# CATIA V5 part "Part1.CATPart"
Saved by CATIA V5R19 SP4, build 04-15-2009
Part number: Part1
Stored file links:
  C:\Users\Romain\Desktop\projet CFAO\Part1.CATPart

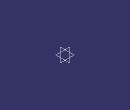
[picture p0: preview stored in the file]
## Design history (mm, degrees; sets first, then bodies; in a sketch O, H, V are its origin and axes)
Body1 (main body)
